VERSION 5.7 ;
BUSBITCHARS "[]" ;
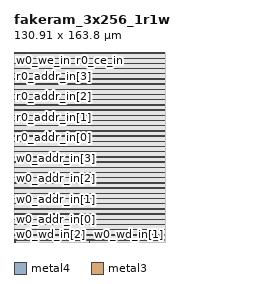
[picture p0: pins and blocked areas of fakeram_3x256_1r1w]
MACRO fakeram_3x256_1r1w
  FOREIGN fakeram_3x256_1r1w 0 0 ;
  SYMMETRY X Y R90 ;
  SIZE 130.910 BY 163.800 ;
  CLASS BLOCK ;
  PIN w0_wd_in[0]
    DIRECTION INPUT ;
    USE SIGNAL ;
    SHAPE ABUTMENT ;
    PORT
      LAYER metal4 ;
      RECT 0.000 1.645 0.210 1.715 ;
    END
  END w0_wd_in[0]
  PIN w0_wd_in[1]
    DIRECTION INPUT ;
    USE SIGNAL ;
    SHAPE ABUTMENT ;
    PORT
      LAYER metal4 ;
      RECT 130.700 1.645 130.910 1.715 ;
    END
  END w0_wd_in[1]
  PIN w0_wd_in[2]
    DIRECTION OUTPUT ;
    USE SIGNAL ;
    SHAPE ABUTMENT ;
    PORT
      LAYER metal3 ;
      RECT 0.805 0.000 0.875 0.210 ;
    END
  END w0_wd_in[2]
  PIN r0_rd_out[0]
    DIRECTION OUTPUT ;
    USE SIGNAL ;
    SHAPE ABUTMENT ;
    PORT
      LAYER metal3 ;
      RECT 33.005 0.000 33.075 0.210 ;
    END
  END r0_rd_out[0]
  PIN r0_rd_out[1]
    DIRECTION OUTPUT ;
    USE SIGNAL ;
    SHAPE ABUTMENT ;
    PORT
      LAYER metal3 ;
      RECT 65.205 0.000 65.275 0.210 ;
    END
  END r0_rd_out[1]
  PIN r0_rd_out[2]
    DIRECTION OUTPUT ;
    USE SIGNAL ;
    SHAPE ABUTMENT ;
    PORT
      LAYER metal3 ;
      RECT 0.805 163.590 0.875 163.800 ;
    END
  END r0_rd_out[2]
  PIN w0_addr_in[0]
    DIRECTION INPUT ;
    USE SIGNAL ;
    SHAPE ABUTMENT ;
    PORT
      LAYER metal4 ;
      RECT 0.000 19.285 0.210 19.355 ;
    END
  END w0_addr_in[0]
  PIN w0_addr_in[1]
    DIRECTION INPUT ;
    USE SIGNAL ;
    SHAPE ABUTMENT ;
    PORT
      LAYER metal4 ;
      RECT 0.000 36.925 0.210 36.995 ;
    END
  END w0_addr_in[1]
  PIN w0_addr_in[2]
    DIRECTION INPUT ;
    USE SIGNAL ;
    SHAPE ABUTMENT ;
    PORT
      LAYER metal4 ;
      RECT 0.000 54.565 0.210 54.635 ;
    END
  END w0_addr_in[2]
  PIN w0_addr_in[3]
    DIRECTION INPUT ;
    USE SIGNAL ;
    SHAPE ABUTMENT ;
    PORT
      LAYER metal4 ;
      RECT 0.000 72.205 0.210 72.275 ;
    END
  END w0_addr_in[3]
  PIN w0_addr_in[4]
    DIRECTION INPUT ;
    USE SIGNAL ;
    SHAPE ABUTMENT ;
    PORT
      LAYER metal4 ;
      RECT 130.700 19.285 130.910 19.355 ;
    END
  END w0_addr_in[4]
  PIN w0_addr_in[5]
    DIRECTION INPUT ;
    USE SIGNAL ;
    SHAPE ABUTMENT ;
    PORT
      LAYER metal4 ;
      RECT 130.700 36.925 130.910 36.995 ;
    END
  END w0_addr_in[5]
  PIN w0_addr_in[6]
    DIRECTION INPUT ;
    USE SIGNAL ;
    SHAPE ABUTMENT ;
    PORT
      LAYER metal4 ;
      RECT 130.700 54.565 130.910 54.635 ;
    END
  END w0_addr_in[6]
  PIN w0_addr_in[7]
    DIRECTION INPUT ;
    USE SIGNAL ;
    SHAPE ABUTMENT ;
    PORT
      LAYER metal4 ;
      RECT 130.700 72.205 130.910 72.275 ;
    END
  END w0_addr_in[7]
  PIN r0_addr_in[0]
    DIRECTION INPUT ;
    USE SIGNAL ;
    SHAPE ABUTMENT ;
    PORT
      LAYER metal4 ;
      RECT 0.000 89.845 0.210 89.915 ;
    END
  END r0_addr_in[0]
  PIN r0_addr_in[1]
    DIRECTION INPUT ;
    USE SIGNAL ;
    SHAPE ABUTMENT ;
    PORT
      LAYER metal4 ;
      RECT 0.000 107.485 0.210 107.555 ;
    END
  END r0_addr_in[1]
  PIN r0_addr_in[2]
    DIRECTION INPUT ;
    USE SIGNAL ;
    SHAPE ABUTMENT ;
    PORT
      LAYER metal4 ;
      RECT 0.000 125.125 0.210 125.195 ;
    END
  END r0_addr_in[2]
  PIN r0_addr_in[3]
    DIRECTION INPUT ;
    USE SIGNAL ;
    SHAPE ABUTMENT ;
    PORT
      LAYER metal4 ;
      RECT 0.000 142.765 0.210 142.835 ;
    END
  END r0_addr_in[3]
  PIN r0_addr_in[4]
    DIRECTION INPUT ;
    USE SIGNAL ;
    SHAPE ABUTMENT ;
    PORT
      LAYER metal4 ;
      RECT 130.700 89.845 130.910 89.915 ;
    END
  END r0_addr_in[4]
  PIN r0_addr_in[5]
    DIRECTION INPUT ;
    USE SIGNAL ;
    SHAPE ABUTMENT ;
    PORT
      LAYER metal4 ;
      RECT 130.700 107.485 130.910 107.555 ;
    END
  END r0_addr_in[5]
  PIN r0_addr_in[6]
    DIRECTION INPUT ;
    USE SIGNAL ;
    SHAPE ABUTMENT ;
    PORT
      LAYER metal4 ;
      RECT 130.700 125.125 130.910 125.195 ;
    END
  END r0_addr_in[6]
  PIN r0_addr_in[7]
    DIRECTION INPUT ;
    USE SIGNAL ;
    SHAPE ABUTMENT ;
    PORT
      LAYER metal4 ;
      RECT 130.700 142.765 130.910 142.835 ;
    END
  END r0_addr_in[7]
  PIN w0_we_in
    DIRECTION INPUT ;
    USE SIGNAL ;
    SHAPE ABUTMENT ;
    PORT
      LAYER metal3 ;
      RECT 19.145 163.590 19.215 163.800 ;
    END
  END w0_we_in
  PIN w0_ce_in
    DIRECTION INPUT ;
    USE SIGNAL ;
    SHAPE ABUTMENT ;
    PORT
      LAYER metal3 ;
      RECT 37.485 163.590 37.555 163.800 ;
    END
  END w0_ce_in
  PIN w0_clk
    DIRECTION INPUT ;
    USE SIGNAL ;
    SHAPE ABUTMENT ;
    PORT
      LAYER metal3 ;
      RECT 55.825 163.590 55.895 163.800 ;
    END
  END w0_clk
  PIN r0_ce_in
    DIRECTION INPUT ;
    USE SIGNAL ;
    SHAPE ABUTMENT ;
    PORT
      LAYER metal3 ;
      RECT 74.165 163.590 74.235 163.800 ;
    END
  END r0_ce_in
  PIN r0_clk
    DIRECTION INPUT ;
    USE SIGNAL ;
    SHAPE ABUTMENT ;
    PORT
      LAYER metal3 ;
      RECT 92.505 163.590 92.575 163.800 ;
    END
  END r0_clk
  PIN VSS
    DIRECTION INOUT ;
    USE GROUND ;
    PORT
      LAYER metal4 ;
      RECT 0.840 1.540 130.070 1.820 ;
      RECT 0.840 6.020 130.070 6.300 ;
      RECT 0.840 10.500 130.070 10.780 ;
      RECT 0.840 14.980 130.070 15.260 ;
      RECT 0.840 19.460 130.070 19.740 ;
      RECT 0.840 23.940 130.070 24.220 ;
      RECT 0.840 28.420 130.070 28.700 ;
      RECT 0.840 32.900 130.070 33.180 ;
      RECT 0.840 37.380 130.070 37.660 ;
      RECT 0.840 41.860 130.070 42.140 ;
      RECT 0.840 46.340 130.070 46.620 ;
      RECT 0.840 50.820 130.070 51.100 ;
      RECT 0.840 55.300 130.070 55.580 ;
      RECT 0.840 59.780 130.070 60.060 ;
      RECT 0.840 64.260 130.070 64.540 ;
      RECT 0.840 68.740 130.070 69.020 ;
      RECT 0.840 73.220 130.070 73.500 ;
      RECT 0.840 77.700 130.070 77.980 ;
      RECT 0.840 82.180 130.070 82.460 ;
      RECT 0.840 86.660 130.070 86.940 ;
      RECT 0.840 91.140 130.070 91.420 ;
      RECT 0.840 95.620 130.070 95.900 ;
      RECT 0.840 100.100 130.070 100.380 ;
      RECT 0.840 104.580 130.070 104.860 ;
      RECT 0.840 109.060 130.070 109.340 ;
      RECT 0.840 113.540 130.070 113.820 ;
      RECT 0.840 118.020 130.070 118.300 ;
      RECT 0.840 122.500 130.070 122.780 ;
      RECT 0.840 126.980 130.070 127.260 ;
      RECT 0.840 131.460 130.070 131.740 ;
      RECT 0.840 135.940 130.070 136.220 ;
      RECT 0.840 140.420 130.070 140.700 ;
      RECT 0.840 144.900 130.070 145.180 ;
      RECT 0.840 149.380 130.070 149.660 ;
      RECT 0.840 153.860 130.070 154.140 ;
      RECT 0.840 158.340 130.070 158.620 ;
      RECT 0.840 162.820 130.070 163.100 ;
    END
  END VSS
  PIN VDD
    DIRECTION INOUT ;
    USE POWER ;
    PORT
      LAYER metal4 ;
      RECT 0.840 1.540 130.070 1.820 ;
      RECT 0.840 6.020 130.070 6.300 ;
      RECT 0.840 10.500 130.070 10.780 ;
      RECT 0.840 14.980 130.070 15.260 ;
      RECT 0.840 19.460 130.070 19.740 ;
      RECT 0.840 23.940 130.070 24.220 ;
      RECT 0.840 28.420 130.070 28.700 ;
      RECT 0.840 32.900 130.070 33.180 ;
      RECT 0.840 37.380 130.070 37.660 ;
      RECT 0.840 41.860 130.070 42.140 ;
      RECT 0.840 46.340 130.070 46.620 ;
      RECT 0.840 50.820 130.070 51.100 ;
      RECT 0.840 55.300 130.070 55.580 ;
      RECT 0.840 59.780 130.070 60.060 ;
      RECT 0.840 64.260 130.070 64.540 ;
      RECT 0.840 68.740 130.070 69.020 ;
      RECT 0.840 73.220 130.070 73.500 ;
      RECT 0.840 77.700 130.070 77.980 ;
      RECT 0.840 82.180 130.070 82.460 ;
      RECT 0.840 86.660 130.070 86.940 ;
      RECT 0.840 91.140 130.070 91.420 ;
      RECT 0.840 95.620 130.070 95.900 ;
      RECT 0.840 100.100 130.070 100.380 ;
      RECT 0.840 104.580 130.070 104.860 ;
      RECT 0.840 109.060 130.070 109.340 ;
      RECT 0.840 113.540 130.070 113.820 ;
      RECT 0.840 118.020 130.070 118.300 ;
      RECT 0.840 122.500 130.070 122.780 ;
      RECT 0.840 126.980 130.070 127.260 ;
      RECT 0.840 131.460 130.070 131.740 ;
      RECT 0.840 135.940 130.070 136.220 ;
      RECT 0.840 140.420 130.070 140.700 ;
      RECT 0.840 144.900 130.070 145.180 ;
      RECT 0.840 149.380 130.070 149.660 ;
      RECT 0.840 153.860 130.070 154.140 ;
      RECT 0.840 158.340 130.070 158.620 ;
      RECT 0.840 162.820 130.070 163.100 ;
    END
  END VDD
  OBS
    LAYER metal1 ;
    RECT 0 0 130.910 163.800 ;
    LAYER metal2 ;
    RECT 0 0 130.910 163.800 ;
    LAYER metal3 ;
    RECT 0 0 130.910 163.800 ;
    LAYER metal4 ;
    RECT 0 0 130.910 163.800 ;
    LAYER OVERLAP ;
    RECT 0 0 130.910 163.800 ;
  END
END fakeram_3x256_1r1w

END LIBRARY
